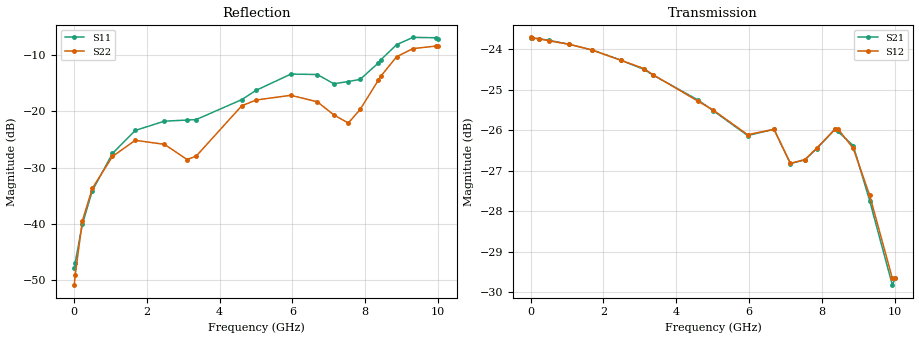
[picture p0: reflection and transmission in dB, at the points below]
! Device ID: PE43704
! Dir: z:\PE43704\PE43704_Char_1_20130516\PE43704\AMB\3p400V\22p75dB
! Serial: 14
! Insertion: A
! Impedance: 50 ohm
! Temp: Amb
! VDD: 3.400V
! Attenuation Step: 22.75dB
! IDD: 1.140390e-01mA
#  Hz  S  RI  R  50
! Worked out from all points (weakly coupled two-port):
!   401 points, 10 MHz to 10.01 GHz, reference 50 ohm
!   highest |S21| = -23.71 dB at 35 MHz (marker M1); lowest = -29.8 dB at 9.935 GHz (marker M2)
!   lowest |S11| = -47.8 dB at 10 MHz (marker M3), VSWR 1.01, Z = 50.4 + j0.0397 ohm
!   |S11| at or under -10 dB: start of sweep to 8.554 GHz
!   |S22| runs from -50.8 to -8.4 dB; largest |S21 - S12| = 0.00067
!   S11 on the Smith chart (normalised r, x): 10 MHz: 1.01, +0.00; 4.61 GHz: 0.79, +0.08; 8.435 GHz: 0.76, +0.46; 9.31 GHz: 0.51, +0.52; 10.01 GHz: 0.44, +0.31
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1e7  0.00406 0.000394  0.0652 -0.000226  0.0653 -0.000153  0.00284 0.000412
3.5e7  0.00422 0.00154  0.0652 -0.000711  0.0652 -0.000716  0.0031 0.00162
2.35e8  0.00209 0.00977  0.0649 -0.00442  0.0649 -0.00437  0.00134 0.0106
5.1e8  -0.00588 0.0189  0.0641 -0.00922  0.064 -0.0092  -0.00598 0.0199
1.06e9  -0.0354 0.0229  0.0613 -0.0185  0.0613 -0.0185  -0.0315 0.0241
1.685e9  -0.0672 0.00611  0.0564 -0.0281  0.0564 -0.0281  -0.0546 0.00776
2.485e9  -0.0796 -0.0175  0.0478 -0.0382  0.0477 -0.0383  -0.0504 -0.00656
3.11e9  -0.0815 -0.0177  0.0398 -0.0444  0.04 -0.0444  -0.0369 0.00503
3.36e9  -0.0835 -0.0114  0.0363 -0.0461  0.0364 -0.0461  -0.0374 0.0141
4.61e9  -0.1168 0.0488  0.0195 -0.051  0.0195 -0.0508  -0.0909 0.0648
5.01e9  -0.1364 0.0701  0.0152 -0.0508  0.0152 -0.0509  -0.109 0.0626
5.96e9  -0.1873 0.1019  0.00424 -0.0492  0.00444 -0.0493  -0.1279 0.0525
6.685e9  -0.1885 0.0955  -0.00264 -0.0502  -0.00252 -0.0502  -0.1131 0.0431
7.135e9  -0.156 0.0795  -0.00898 -0.0447  -0.00912 -0.0447  -0.0781 0.0502
7.535e9  -0.1352 0.1233  -0.00995 -0.045  -0.0101 -0.045  -0.0458 0.0637
7.86e9  -0.0955 0.1659  -0.0122 -0.046  -0.0121 -0.0461  -0.0362 0.0971
8.36e9  -0.0616 0.2603  -0.0218 -0.0453  -0.0218 -0.0453  -0.0547 0.18
8.435e9  -0.0626 0.2799  -0.0231 -0.0443  -0.0232 -0.0447  -0.0642 0.1952
8.86e9  -0.1019 0.3746  -0.0302 -0.0373  -0.0296 -0.0373  -0.1251 0.2762
9.31e9  -0.1834 0.4119  -0.0299 -0.0281  -0.0304 -0.0285  -0.2173 0.2852
9.935e9  -0.3168 0.3161  -0.0211 -0.0244  -0.0217 -0.0247  -0.3501 0.1408
1.001e10  -0.3284 0.2905  -0.0203 -0.0259  -0.0205 -0.0257  -0.3594 0.1111
